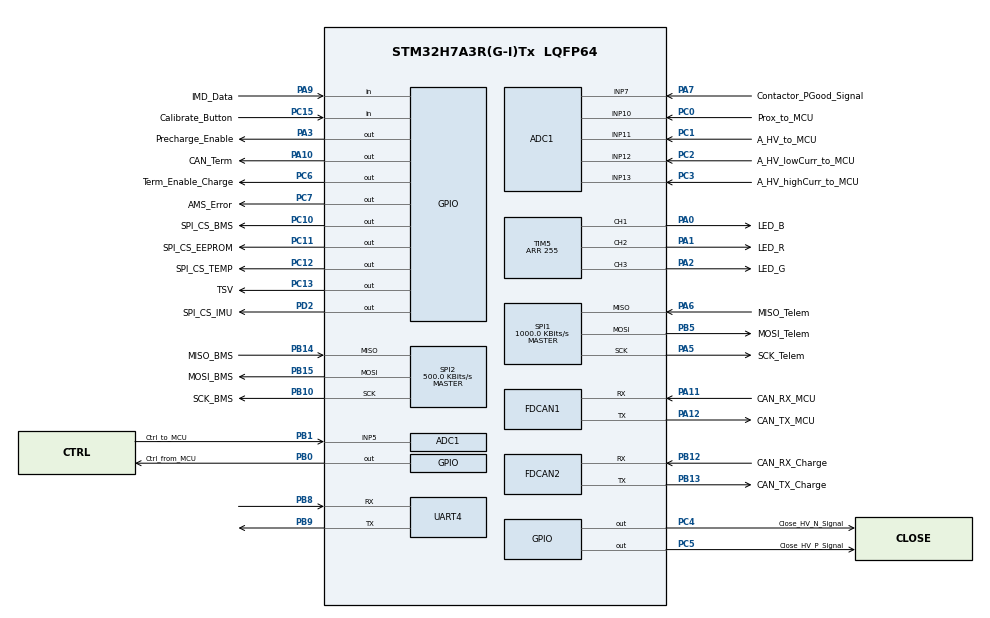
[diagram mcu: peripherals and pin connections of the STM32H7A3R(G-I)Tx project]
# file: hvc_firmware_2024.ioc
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ADC1.Channel-0\#ChannelRegularConversion=ADC_CHANNEL_7
ADC1.Channel-1\#ChannelRegularConversion=ADC_CHANNEL_5
ADC1.Channel-2\#ChannelRegularConversion=ADC_CHANNEL_10
ADC1.Channel-3\#ChannelRegularConversion=ADC_CHANNEL_11
ADC1.Channel-4\#ChannelRegularConversion=ADC_CHANNEL_12
ADC1.Channel-5\#ChannelRegularConversion=ADC_CHANNEL_13
ADC1.ContinuousConvMode=ENABLE
ADC1.ConversionDataManagement=ADC_CONVERSIONDATA_DMA_CIRCULAR
ADC1.EOCSelection=ADC_EOC_SEQ_CONV
ADC1.NbrOfConversion=6
ADC1.NbrOfConversionFlag=1
ADC1.OffsetNumber-0\#ChannelRegularConversion=ADC_OFFSET_NONE
ADC1.OffsetNumber-1\#ChannelRegularConversion=ADC_OFFSET_NONE
ADC1.OffsetNumber-2\#ChannelRegularConversion=ADC_OFFSET_NONE
ADC1.OffsetNumber-3\#ChannelRegularConversion=ADC_OFFSET_NONE
ADC1.OffsetNumber-4\#ChannelRegularConversion=ADC_OFFSET_NONE
ADC1.OffsetNumber-5\#ChannelRegularConversion=ADC_OFFSET_NONE
ADC1.OffsetSignedSaturation-0\#ChannelRegularConversion=DISABLE
ADC1.OffsetSignedSaturation-1\#ChannelRegularConversion=DISABLE
ADC1.OffsetSignedSaturation-2\#ChannelRegularConversion=DISABLE
ADC1.OffsetSignedSaturation-3\#ChannelRegularConversion=DISABLE
ADC1.OffsetSignedSaturation-4\#ChannelRegularConversion=DISABLE
ADC1.OffsetSignedSaturation-5\#ChannelRegularConversion=DISABLE
ADC1.OversamplingMode=ENABLE
ADC1.Rank-0\#ChannelRegularConversion=1
ADC1.Rank-1\#ChannelRegularConversion=2
ADC1.Rank-2\#ChannelRegularConversion=3
ADC1.Rank-3\#ChannelRegularConversion=4
ADC1.Rank-4\#ChannelRegularConversion=5
ADC1.Rank-5\#ChannelRegularConversion=6
ADC1.Ratio=16
ADC1.RightBitShift=ADC_RIGHTBITSHIFT_4
ADC1.SamplingTime-0\#ChannelRegularConversion=ADC_SAMPLETIME_1CYCLE_5
ADC1.SamplingTime-1\#ChannelRegularConversion=ADC_SAMPLETIME_1CYCLE_5
ADC1.SamplingTime-2\#ChannelRegularConversion=ADC_SAMPLETIME_1CYCLE_5
ADC1.SamplingTime-3\#ChannelRegularConversion=ADC_SAMPLETIME_1CYCLE_5
ADC1.SamplingTime-4\#ChannelRegularConversion=ADC_SAMPLETIME_1CYCLE_5
ADC1.SamplingTime-5\#ChannelRegularConversion=ADC_SAMPLETIME_1CYCLE_5
ADC1.master=1
Dma.ADC1.0.Direction=DMA_PERIPH_TO_MEMORY
Dma.ADC1.0.EventEnable=DISABLE
Dma.ADC1.0.FIFOMode=DMA_FIFOMODE_DISABLE
Dma.ADC1.0.Instance=DMA1_Stream0
Dma.ADC1.0.MemDataAlignment=DMA_MDATAALIGN_HALFWORD
Dma.ADC1.0.MemInc=DMA_MINC_ENABLE
Dma.ADC1.0.Mode=DMA_CIRCULAR
Dma.ADC1.0.PeriphDataAlignment=DMA_PDATAALIGN_HALFWORD
Dma.ADC1.0.PeriphInc=DMA_PINC_DISABLE
Dma.ADC1.0.Polarity=HAL_DMAMUX_REQ_GEN_RISING
Dma.ADC1.0.Priority=DMA_PRIORITY_LOW
Dma.ADC1.0.RequestNumber=1
Dma.ADC1.0.SignalID=NONE
Dma.ADC1.0.SyncEnable=DISABLE
Dma.ADC1.0.SyncPolarity=HAL_DMAMUX_SYNC_NO_EVENT
Dma.ADC1.0.SyncRequestNumber=1
Dma.ADC1.0.SyncSignalID=NONE
Dma.Request0=ADC1
FDCAN1.CalculateBaudRateNominal=1000000
FDCAN1.CalculateTimeBitNominal=1000
FDCAN1.CalculateTimeQuantumNominal=62.5
FDCAN1.DataSyncJumpWidth=3
FDCAN1.DataTimeSeg1=13
FDCAN1.DataTimeSeg2=2
FDCAN1.NominalPrescaler=1
FDCAN1.NominalSyncJumpWidth=3
FDCAN1.NominalTimeSeg1=13
FDCAN1.RxFifo0ElmtsNbr=64
FDCAN1.TxFifoQueueElmtsNbr=16
FDCAN1.TxFifoQueueMode=FDCAN_TX_FIFO_OPERATION
FDCAN2.CalculateBaudRateNominal=500000
FDCAN2.CalculateTimeBitNominal=2000
FDCAN2.CalculateTimeQuantumNominal=125.0
FDCAN2.DataSyncJumpWidth=3
FDCAN2.DataTimeSeg1=13
FDCAN2.DataTimeSeg2=2
FDCAN2.NominalPrescaler=2
FDCAN2.NominalSyncJumpWidth=3
FDCAN2.NominalTimeSeg1=13
FDCAN2.RxFifo0ElmtsNbr=64
FDCAN2.TxFifoQueueElmtsNbr=16
Mcu.Family=STM32H7
Mcu.Name=STM32H7A3R(G-I)Tx
Mcu.Package=LQFP64
NVIC.DMA1_Stream0_IRQn=true\:0\:0\:false\:false\:true\:false\:true\:true
NVIC.PriorityGroup=NVIC_PRIORITYGROUP_4
PA0.GPIO_Label=LED_B
PA0.GPIO_ModeDefaultPP=GPIO_MODE_AF_OD
PA0.GPIO_Speed=GPIO_SPEED_FREQ_VERY_HIGH
PA0.Signal=S_TIM5_CH1
PA1.GPIO_Label=LED_R
PA1.GPIO_ModeDefaultPP=GPIO_MODE_AF_OD
PA1.GPIO_Speed=GPIO_SPEED_FREQ_VERY_HIGH
PA1.Signal=S_TIM5_CH2
PA10.GPIO_Label=CAN_Term
PA10.PinState=GPIO_PIN_RESET
PA10.Signal=GPIO_Output
PA11.GPIO_Label=CAN_RX_MCU
PA11.GPIO_Speed=GPIO_SPEED_FREQ_VERY_HIGH
PA11.Mode=FDCAN_Activate
PA11.Signal=FDCAN1_RX
PA12.GPIO_Label=CAN_TX_MCU
PA12.GPIO_Speed=GPIO_SPEED_FREQ_VERY_HIGH
PA12.Mode=FDCAN_Activate
PA12.Signal=FDCAN1_TX
PA13.Mode=Trace_Asynchronous_SW
PA13.Signal=DEBUG_JTMS-SWDIO
PA14.Mode=Trace_Asynchronous_SW
PA14.Signal=DEBUG_JTCK-SWCLK
PA2.GPIO_Label=LED_G
PA2.GPIO_ModeDefaultPP=GPIO_MODE_AF_OD
PA2.GPIO_Speed=GPIO_SPEED_FREQ_VERY_HIGH
PA2.Signal=S_TIM5_CH3
PA3.GPIO_Label=Precharge_Enable
PA3.Signal=GPIO_Output
PA5.GPIO_Label=SCK_Telem
PA5.GPIO_PuPd=GPIO_PULLUP
PA5.GPIO_Speed=GPIO_SPEED_FREQ_VERY_HIGH
PA5.Mode=Full_Duplex_Master
PA5.Signal=SPI1_SCK
PA6.GPIO_Label=MISO_Telem
PA6.GPIO_PuPd=GPIO_PULLUP
PA6.GPIO_Speed=GPIO_SPEED_FREQ_VERY_HIGH
PA6.Mode=Full_Duplex_Master
PA6.Signal=SPI1_MISO
PA7.GPIO_Label=Contactor_PGood_Signal
PA7.Signal=ADCx_INP7
PA9.GPIO_Label=IMD_Data
PA9.Signal=GPIO_Input
PB0.GPIO_Label=Ctrl_from_MCU
PB0.Signal=GPIO_Output
PB1.GPIO_Label=Ctrl_to_MCU
PB1.Signal=ADCx_INP5
PB10.GPIO_Label=SCK_BMS
PB10.GPIO_PuPd=GPIO_PULLUP
PB10.GPIO_Speed=GPIO_SPEED_FREQ_VERY_HIGH
PB10.Mode=Full_Duplex_Master
PB10.Signal=SPI2_SCK
PB12.GPIO_Label=CAN_RX_Charge
PB12.GPIO_Speed=GPIO_SPEED_FREQ_VERY_HIGH
PB12.Mode=FDCAN_Activate
PB12.Signal=FDCAN2_RX
PB13.GPIO_Label=CAN_TX_Charge
PB13.GPIO_Speed=GPIO_SPEED_FREQ_VERY_HIGH
PB13.Mode=FDCAN_Activate
PB13.Signal=FDCAN2_TX
PB14.GPIO_Label=MISO_BMS
PB14.GPIO_PuPd=GPIO_PULLUP
PB14.GPIO_Speed=GPIO_SPEED_FREQ_VERY_HIGH
PB14.Mode=Full_Duplex_Master
PB14.Signal=SPI2_MISO
PB15.GPIO_Label=MOSI_BMS
PB15.GPIO_PuPd=GPIO_PULLUP
PB15.GPIO_Speed=GPIO_SPEED_FREQ_VERY_HIGH
PB15.Mode=Full_Duplex_Master
PB15.Signal=SPI2_MOSI
PB3.Mode=Trace_Asynchronous_SW
PB3.Signal=DEBUG_JTDO-SWO
PB5.GPIO_Label=MOSI_Telem
PB5.GPIO_PuPd=GPIO_PULLUP
PB5.GPIO_Speed=GPIO_SPEED_FREQ_VERY_HIGH
PB5.Mode=Full_Duplex_Master
PB5.Signal=SPI1_MOSI
PB8.Mode=Asynchronous
PB8.Signal=UART4_RX
PB9.Mode=Asynchronous
PB9.Signal=UART4_TX
PC0.GPIO_Label=Prox_to_MCU
PC0.Signal=ADCx_INP10
PC1.GPIO_Label=A_HV_to_MCU
PC1.Signal=ADCx_INP11
PC10.GPIO_Label=SPI_CS_BMS
PC10.GPIO_Speed=GPIO_SPEED_FREQ_VERY_HIGH
PC10.PinState=GPIO_PIN_SET
PC10.Signal=GPIO_Output
PC11.GPIO_Label=SPI_CS_EEPROM
PC11.GPIO_Speed=GPIO_SPEED_FREQ_VERY_HIGH
PC11.PinState=GPIO_PIN_SET
PC11.Signal=GPIO_Output
PC12.GPIO_Label=SPI_CS_TEMP
PC12.GPIO_Speed=GPIO_SPEED_FREQ_VERY_HIGH
PC12.PinState=GPIO_PIN_SET
PC12.Signal=GPIO_Output
PC13.GPIO_Label=TSV
PC13.Signal=GPIO_Output
PC15-OSC32_OUT.GPIO_Label=Calibrate_Button
PC15-OSC32_OUT.Signal=GPIO_Input
PC2.GPIO_Label=A_HV_lowCurr_to_MCU
PC2.Signal=ADCx_INP12
PC3.GPIO_Label=A_HV_highCurr_to_MCU
PC3.Signal=ADCx_INP13
PC4.GPIO_Label=Close_HV_N_Signal
PC4.Signal=GPIO_Output
PC5.GPIO_Label=Close_HV_P_Signal
PC5.Signal=GPIO_Output
PC6.GPIO_Label=Term_Enable_Charge
PC6.PinState=GPIO_PIN_SET
PC6.Signal=GPIO_Output
PC7.GPIO_Label=AMS_Error
PC7.Signal=GPIO_Output
PD2.GPIO_Label=SPI_CS_IMU
PD2.GPIO_Speed=GPIO_SPEED_FREQ_VERY_HIGH
PD2.PinState=GPIO_PIN_SET
PD2.Signal=GPIO_Output
PH0-OSC_IN.Mode=HSE-External-Oscillator
PH0-OSC_IN.Signal=RCC_OSC_IN
PH1-OSC_OUT.Mode=HSE-External-Oscillator
PH1-OSC_OUT.Signal=RCC_OSC_OUT
ProjectManager.HeapSize=0x200
ProjectManager.StackSize=0x400
ProjectManager.TargetToolchain=STM32CubeIDE
RCC.ADCFreq_Value=3686400
RCC.APB1Freq_Value=140000000
RCC.APB2Freq_Value=140000000
RCC.APB3Freq_Value=140000000
RCC.APB4Freq_Value=140000000
RCC.CDPPRE=RCC_APB3_DIV2
RCC.CDPPRE1=RCC_APB1_DIV2
RCC.CDPPRE2=RCC_APB2_DIV2
RCC.CortexFreq_Value=280000000
RCC.DIVM1=1
RCC.DIVM2=10
RCC.DIVM3=1
RCC.DIVN1=35
RCC.DIVN2=288
RCC.DIVN3=8
RCC.DIVP2=125
RCC.DIVQ1=35
RCC.HCLKFreq_Value=280000000
RCC.HSE_VALUE=16000000
RCC.HSIDiv=RCC_PLLSAIDIVR_4
RCC.SPI123CLockSelection=RCC_SPI123CLKSOURCE_PLL3
RCC.SRDPPRE=RCC_APB4_DIV2
RCC.SYSCLKFreq_VALUE=280000000
RCC.SYSCLKSource=RCC_SYSCLKSOURCE_PLLCLK
RCC.USBFreq_Value=16000000
SH.ADCx_INP10.0=ADC1_INP10,IN10-Single-Ended
SH.ADCx_INP11.0=ADC1_INP11,IN11-Single-Ended
SH.ADCx_INP12.0=ADC1_INP12,IN12-Single-Ended
SH.ADCx_INP13.0=ADC1_INP13,IN13-Single-Ended
SH.ADCx_INP5.0=ADC1_INP5,IN5-Single-Ended
SH.ADCx_INP7.0=ADC1_INP7,IN7-Single-Ended
SH.S_TIM5_CH1.0=TIM5_CH1,PWM Generation1 CH1
SH.S_TIM5_CH2.0=TIM5_CH2,PWM Generation2 CH2
SH.S_TIM5_CH3.0=TIM5_CH3,PWM Generation3 CH3
SPI1.BaudRatePrescaler=SPI_BAUDRATEPRESCALER_64
SPI1.CLKPhase=SPI_PHASE_2EDGE
SPI1.CLKPolarity=SPI_POLARITY_HIGH
SPI1.CalculateBaudRate=1000.0 KBits/s
SPI1.DataSize=SPI_DATASIZE_8BIT
SPI1.Direction=SPI_DIRECTION_2LINES
SPI1.Mode=SPI_MODE_MASTER
SPI1.VirtualType=VM_MASTER
SPI2.BaudRatePrescaler=SPI_BAUDRATEPRESCALER_128
SPI2.CLKPhase=SPI_PHASE_2EDGE
SPI2.CLKPolarity=SPI_POLARITY_HIGH
SPI2.CalculateBaudRate=500.0 KBits/s
SPI2.DataSize=SPI_DATASIZE_8BIT
SPI2.Direction=SPI_DIRECTION_2LINES
SPI2.MasterKeepIOState=SPI_MASTER_KEEP_IO_STATE_ENABLE
SPI2.Mode=SPI_MODE_MASTER
SPI2.NSSPMode=SPI_NSS_PULSE_ENABLE
SPI2.VirtualType=VM_MASTER
TIM3.Period=255
TIM3.Prescaler=40
TIM5.Channel-PWM\ Generation1\ CH1=TIM_CHANNEL_1
TIM5.Channel-PWM\ Generation2\ CH2=TIM_CHANNEL_2
TIM5.Channel-PWM\ Generation3\ CH3=TIM_CHANNEL_3
TIM5.OCFastMode_PWM-PWM\ Generation1\ CH1=TIM_OCFAST_ENABLE
TIM5.OCFastMode_PWM-PWM\ Generation2\ CH2=TIM_OCFAST_ENABLE
TIM5.OCFastMode_PWM-PWM\ Generation3\ CH3=TIM_OCFAST_ENABLE
TIM5.OCPolarity_1=TIM_OCPOLARITY_LOW
TIM5.OCPolarity_2=TIM_OCPOLARITY_LOW
TIM5.OCPolarity_3=TIM_OCPOLARITY_LOW
TIM5.Period=255
VP_TIM3_VS_ClockSourceINT.Mode=Internal
VP_TIM5_VS_ClockSourceINT.Mode=Internal
board=custom

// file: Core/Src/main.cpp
/* USER CODE BEGIN Header */
/**
  ******************************************************************************
  * @file           : main.c
  * @brief          : Main program body
  ******************************************************************************
  * @attention
  *
  * Copyright (c) 2023 STMicroelectronics.
  * All rights reserved.
  *
  * This software is licensed under terms that can be found in the LICENSE file
  * in the root directory of this software component.
  * If no LICENSE file comes with this software, it is provided AS-IS.
  *
  ******************************************************************************
  */
/* USER CODE END Header */
#include "main.h"
#include "adc.h"
#include "dma.h"
#include "fdcan.h"
#include "spi.h"
#include "tim.h"
#include "usart.h"
#include "gpio.h"

/* USER CODE BEGIN Includes */
#include "imd.h"
#include "state_machine.h"
#include "vcu.h"
#include "charging.h"
#include "vsense.h"
#include "isense.h"
#include "tsense.h"
#include "cells.h"
#include "LonghornLib/clock.h"
#include "fans.h"
#include "LonghornLib/led.h"
#include "usb.h"
#include "LonghornLib/imu.h"
#include "contactors.h"
#include "LonghornLib/angel_can.h"
/* USER CODE END Includes */

void SystemClock_Config(void);
void PeriphCommonClock_Config(void);

/* USER CODE BEGIN 0 */
static bool hvOk = true;
static bool hvOkEver = false;
static float hvFaultTimer = 0;
static int state = STATE_NOT_ENERGIZED;
/* USER CODE END 0 */

int main(void)
{

  /* MCU Configuration--------------------------------------------------------*/

  /* Reset of all peripherals, Initializes the Flash interface and the Systick. */
  HAL_Init();

  /* Configure the system clock */
  SystemClock_Config();

/* Configure the peripherals common clocks */
  PeriphCommonClock_Config();

  /* Initialize all configured peripherals */
  MX_GPIO_Init();
  MX_DMA_Init();
  MX_FDCAN1_Init();
  MX_ADC1_Init();
  MX_SPI1_Init();
  MX_TIM3_Init();
  MX_SPI2_Init();
  MX_TIM5_Init();
  MX_UART4_Init();
  MX_FDCAN2_Init();
  /* USER CODE BEGIN 2 */
  clock_init();
  led_init();
  can_init(&hfdcan1);

//  tsenseInit();
  chargingInit();
  fansInit();

  vcuInit();
  stateMachineInit();
  cellsInit();

  /* USER CODE END 2 */

  /* Infinite loop */
  while (1) {

    /* USER CODE BEGIN 3 */
    float deltaTime = clock_getDeltaTime();

    volatile bool imdOk = isImdOk();
    volatile bool shutdownClosed = isShutdownClosed() && (clock_getTime() > 1.0f);
    volatile bool chargerPresent = isChargerPluggedIn();

    volatile bool hvOkInstant;

#ifdef PRINT_BMS_DATA
    static int cc = 0;
    cc++;
    bool timeToPrint = (((cc-1) % (270*10)) == 0) && (state != STATE_ENERGIZED);

    if(timeToPrint)
    {
      std::string space, s;

      s = "isospi responsive?";
      println(space);
      println(s);
      println(isIsoSpiResponsive());

      s = "cell voltages ok?";
      println(space);
      println(s);
      println(areCellVoltagesWithinBounds());

      s = "cell temps ok?";
      println(space);
      println(s);
      println(isTempWithinBounds());

      s = "pack voltage ok?";
      println(space);
      println(s);
      println(isPackVoltageWithinBounds());

      s = "pack current ok?";
      println(space);
      println(s);
      println(isPackCurrentWithinBounds());

      s = "imd ok?";
      println(space);
      println(s);
      println(imdOk);

      s = "shutdown closed?";
      println(space);
      println(s);
      println(shutdownClosed);

      s = "charger present?";
      println(space);
      println(s);
      println(chargerPresent);

      s = "voltage";
      std::string voltageMessage = std::to_string(getTractiveVoltage()) + " / " + std::to_string(getPackVoltageFromCells());
      println(space);
      println(s);
      println(voltageMessage);

      println(space);
    }
#endif

    hvOkInstant = isIsoSpiResponsive();
    hvOkInstant = hvOkInstant && isTempWithinBounds();
    hvOkInstant = hvOkInstant && isPackVoltageWithinBounds();
    hvOkInstant = hvOkInstant && isPackCurrentWithinBounds();
    hvOkInstant = hvOkInstant && areCellVoltagesWithinBounds();
    hvOkEver = hvOkEver || hvOkInstant;

    if (hvOkInstant) {
      hvOk = true;
      hvFaultTimer = 0;
    } else {
      hvFaultTimer += deltaTime;
      if (hvFaultTimer > 5.0f) {
        hvOk = false;
      }
    }

    bool amsError = !(hvOk && hvOkEver);
    bool imdError = !imdOk;
    hvOk = hvOk && hvOkEver && imdOk;

    if (clock_getTime() > 6.0f) {
      writeAmsError(amsError);
    }

    state = updateStateMachine(shutdownClosed, hvOk && hvOkEver, chargerPresent, deltaTime);

    volatile float vPack = getPackVoltageFromCells();
    volatile float vSense = getTractiveVoltage();

    // println(vSense);

    cellsPeriodic(state);
    vcuPeriodic(amsError, imdError, state, deltaTime);

    float maxCellMargin = getMaxCellMargin();
    chargingPeriodic(shutdownClosed, state == STATE_CHARGING, amsError, imdError, vPack, maxCellMargin, deltaTime);
    fansPeriodic(deltaTime);
    can_periodic(deltaTime);
    //    tsensePeriodic();

//    uint32_t ics = getNumResponsiveChips();
//    if(ics == 0) {
//      led_set(0.3f, 0, 0);
//    } else if(ics % 2 == 1) {
//      led_set(0.3f, 0.3f, 0);
//    } else if(ics == 2) {
//      led_set(0.3f, 0, 0.3f);
//    } else if(ics == 4) {
//      led_set(0, 0, 0.3f);
//    } else if(ics == 6) {
//      led_set(0, 0.3f, 0.3f);
//    } else if(ics == 8) {
//      led_set(0, 0.3f, 0);
//    } else if(ics == 10) {
//      led_set(0.3f, 0.3f, 0.3f);
//    }
//    println(ics);

    if (hvOk && hvOkEver) {
      if (state == STATE_PRECHARGING) {
        led_set(0.25f, 0.25f, 0);
      } else if (state == STATE_ENERGIZED) {
        led_set(0, 0.4f, 0);
      } else if (state == STATE_CHARGING_PRECHARGING) {
        led_set(0, 0.25f, 0.25f);
      } else if (state == STATE_CHARGING) {
        led_set(0, 0, 0.4f);
      } else { // shutdown circuit open
        led_set(0.3f, 0.3f, 0.3f);
      }
    } else {
      led_set(0.3f, 0, 0);
    }

    HAL_GPIO_WritePin(TSV_GPIO_Port, TSV_Pin,
                      (getTractiveVoltage() > 75.0f) ? GPIO_PIN_SET : GPIO_PIN_RESET);

    HAL_Delay(1);
  }
  /* USER CODE END 3 */
}

void SystemClock_Config(void)
{
  RCC_OscInitTypeDef RCC_OscInitStruct = {0};
  RCC_ClkInitTypeDef RCC_ClkInitStruct = {0};

  /*AXI clock gating */
  RCC->CKGAENR = 0xFFFFFFFF;

  /** Supply configuration update enable
  */
  HAL_PWREx_ConfigSupply(PWR_LDO_SUPPLY);

  /** Configure the main internal regulator output voltage
  */
  __HAL_PWR_VOLTAGESCALING_CONFIG(PWR_REGULATOR_VOLTAGE_SCALE0);

  while(!__HAL_PWR_GET_FLAG(PWR_FLAG_VOSRDY)) {}

  /** Initializes the RCC Oscillators according to the specified parameters
  * in the RCC_OscInitTypeDef structure.
  */
  RCC_OscInitStruct.OscillatorType = RCC_OSCILLATORTYPE_HSI;
  RCC_OscInitStruct.HSIState = RCC_HSI_DIV4;
  RCC_OscInitStruct.HSICalibrationValue = 64;
  RCC_OscInitStruct.PLL.PLLState = RCC_PLL_ON;
  RCC_OscInitStruct.PLL.PLLSource = RCC_PLLSOURCE_HSI;
  RCC_OscInitStruct.PLL.PLLM = 1;
  RCC_OscInitStruct.PLL.PLLN = 35;
  RCC_OscInitStruct.PLL.PLLP = 2;
  RCC_OscInitStruct.PLL.PLLQ = 35;
  RCC_OscInitStruct.PLL.PLLR = 2;
  RCC_OscInitStruct.PLL.PLLRGE = RCC_PLL1VCIRANGE_3;
  RCC_OscInitStruct.PLL.PLLVCOSEL = RCC_PLL1VCOWIDE;
  RCC_OscInitStruct.PLL.PLLFRACN = 0;
  if (HAL_RCC_OscConfig(&RCC_OscInitStruct) != HAL_OK)
  {
    Error_Handler();
  }

  /** Initializes the CPU, AHB and APB buses clocks
  */
  RCC_ClkInitStruct.ClockType = RCC_CLOCKTYPE_HCLK|RCC_CLOCKTYPE_SYSCLK
                              |RCC_CLOCKTYPE_PCLK1|RCC_CLOCKTYPE_PCLK2
                              |RCC_CLOCKTYPE_D3PCLK1|RCC_CLOCKTYPE_D1PCLK1;
  RCC_ClkInitStruct.SYSCLKSource = RCC_SYSCLKSOURCE_PLLCLK;
  RCC_ClkInitStruct.SYSCLKDivider = RCC_SYSCLK_DIV1;
  RCC_ClkInitStruct.AHBCLKDivider = RCC_HCLK_DIV1;
  RCC_ClkInitStruct.APB3CLKDivider = RCC_APB3_DIV2;
  RCC_ClkInitStruct.APB1CLKDivider = RCC_APB1_DIV2;
  RCC_ClkInitStruct.APB2CLKDivider = RCC_APB2_DIV2;
  RCC_ClkInitStruct.APB4CLKDivider = RCC_APB4_DIV2;

  if (HAL_RCC_ClockConfig(&RCC_ClkInitStruct, FLASH_LATENCY_6) != HAL_OK)
  {
    Error_Handler();
  }
}

void PeriphCommonClock_Config(void)
{
  RCC_PeriphCLKInitTypeDef PeriphClkInitStruct = {0};

  /** Initializes the peripherals clock
  */
  PeriphClkInitStruct.PeriphClockSelection = RCC_PERIPHCLK_SPI2|RCC_PERIPHCLK_SPI1;
  PeriphClkInitStruct.PLL3.PLL3M = 1;
  PeriphClkInitStruct.PLL3.PLL3N = 8;
  PeriphClkInitStruct.PLL3.PLL3P = 2;
  PeriphClkInitStruct.PLL3.PLL3Q = 2;
  PeriphClkInitStruct.PLL3.PLL3R = 2;
  PeriphClkInitStruct.PLL3.PLL3RGE = RCC_PLL3VCIRANGE_3;
  PeriphClkInitStruct.PLL3.PLL3VCOSEL = RCC_PLL3VCOWIDE;
  PeriphClkInitStruct.PLL3.PLL3FRACN = 0;
  PeriphClkInitStruct.Spi123ClockSelection = RCC_SPI123CLKSOURCE_PLL3;
  if (HAL_RCCEx_PeriphCLKConfig(&PeriphClkInitStruct) != HAL_OK)
  {
    Error_Handler();
  }
}

void Error_Handler(void)
{
  __disable_irq();
  while (1) {
  }
}
